! (c) 2009  Infineon Technologies AG, Munich
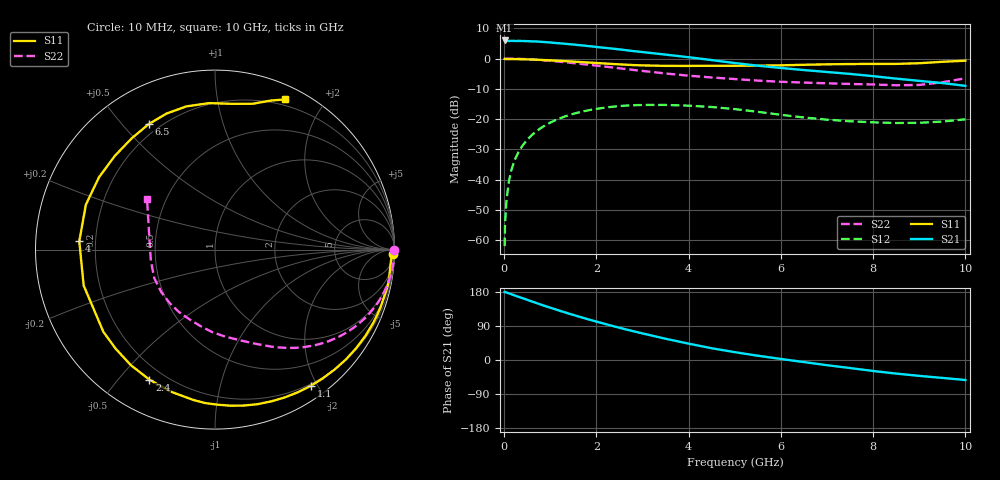
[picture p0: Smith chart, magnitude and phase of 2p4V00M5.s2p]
! Infineon Technologies  Discrete & RF Semiconductors
! BFP420
! VCE =  4.0 V,  IC =  0.5 mA
! Common Emitter S-Parameters:  Nov 2009
# GHz  S  MA  R  50
!  f  S11  S21  S12  S22
! GHz  MAG  ANG  MAG  ANG  MAG  ANG  MAG  ANG
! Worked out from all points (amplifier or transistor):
!   46 points, 10 MHz to 10 GHz, reference 50 ohm
!   highest |S21| = 6.0 dB at 10 MHz (marker M1)
!   |S21| within 3 dB of that: start of sweep to 2.525 GHz
!   unconditionally stable (mu >= 1): 4.482 GHz to end of sweep
!   at 300 MHz: K = 0.02, MSG = 18.5 dB, |S12| = -31.2 dB
!   at 1.7 GHz: K = 0.25, MSG = 10.9 dB, |S12| = -17.5 dB
!   at 10 GHz: K = 1.56, MAG = 1.1 dB, |S12| = -20.1 dB
!   lowest NFmin = 0.68 dB at 900 MHz
!   S11 on the Smith chart (normalised r, x): 10 MHz: 21, -70; 1.1 GHz: 0.17, -1.91; 2.4 GHz: 0.14, -0.61; 4 GHz: 0.14, +0.03; 6.5 GHz: 0.16, +0.59; 10 GHz: 0.14, +1.56
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0.01  0.9922 -1.5  1.994 179.4  0.0008 80.6  0.9992 -0.1
0.02  0.9836 -1.0  1.933 179.5  0.0019 85.3  0.9981 -0.4
0.05  0.9838 -2.6  1.947 178.1  0.0045 86.1  0.9981 -1.2
0.1  0.9812 -5.1  1.956 175.9  0.0091 86.2  0.9982 -2.6
0.15  0.9819 -7.5  1.961 173.8  0.0138 85.1  0.9969 -3.8
0.25  0.9824 -12.4  1.955 169.3  0.023 82.4  0.9933 -6.4
0.4  0.9761 -19.9  1.952 163.1  0.0367 77.8  0.9841 -10.2
0.6  0.9663 -29.9  1.927 154.5  0.0546 71.5  0.9669 -15.2
0.9  0.9438 -45.0  1.87 142.0  0.0798 62.1  0.9316 -22.3
1.1  0.928 -54.9  1.816 134.2  0.0954 56.2  0.9044 -26.7
1.4  0.9016 -69.8  1.734 122.5  0.1163 47.1  0.8595 -33.1
1.7  0.8742 -84.2  1.65 111.7  0.1339 38.6  0.8127 -38.9
2.4  0.8113 -116.8  1.447 88.2  0.1621 20.0  0.7067 -50.8
3  0.7725 -143.6  1.283 70.1  0.1718 5.5  0.6258 -59.8
3.5  0.7586 -164.7  1.164 56.1  0.1718 -5.1  0.568 -67.2
4  0.7575 176.5  1.054 43.1  0.1671 -14.1  0.5224 -74.9
4.5  0.7618 160.8  0.945 31.0  0.1588 -22.4  0.4879 -83.4
5.5  0.7643 137.0  0.764 11.3  0.1323 -34.4  0.4336 -100.8
6.5  0.7907 117.9  0.647 -5.5  0.1067 -38.1  0.4019 -119.7
7  0.8047 109.6  0.601 -13.7  0.0981 -37.0  0.391 -130.0
8.5  0.8177 83.3  0.467 -35.9  0.0864 -28.9  0.3628 -170.0
10  0.9235 65.0  0.355 -52.8  0.0994 -18.5  0.4728 143.3
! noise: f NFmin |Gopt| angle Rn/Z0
0.9  0.68  0.78  35  0.65
1.8  1.42  0.6  75  0.5
2.4  1.57  0.58  98  0.37
3  2.1  0.58  128  0.24
4  2.49  0.57  177  0.09
